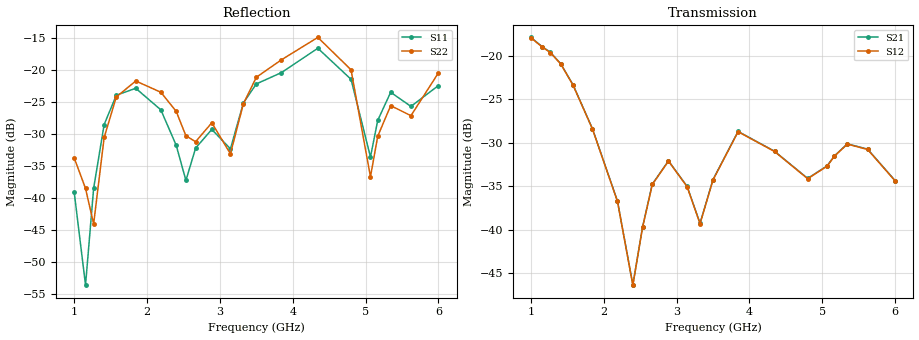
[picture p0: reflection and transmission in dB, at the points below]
!Agilent Technologies,E8364B,MY43040528,A.07.50.67
!Agilent E8364B: A.07.50.67
!Date: Sunday, March 01, 2026 15:36:02
!Correction: S11(Full 2 Port(1,2))
!S21(Full 2 Port(1,2))
!S12(Full 2 Port(1,2))
!S22(Full 2 Port(1,2))
!S2P File: Measurements: S11, S21, S12, S22:
# Hz S  dB  R 50
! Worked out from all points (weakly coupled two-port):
!   451 points, 1 GHz to 6 GHz, reference 50 ohm
!   highest |S21| = -17.88 dB at 1 GHz (marker M1); lowest = -46.4 dB at 2.4 GHz (marker M2)
!   lowest |S11| = -53.6 dB at 1.156 GHz (marker M3), VSWR 1.00, Z = 49.9 + j0.173 ohm
!   |S11| at or under -10 dB: start of sweep to end of sweep
!   |S22| runs from -44.2 to -14.8 dB; largest |S21 - S12| = 0.00053
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1e9  -39.11 33.9  -17.88 27.7  -17.92 27.7  -33.74 -13.1
1.155556e9  -53.64 123.5  -18.95 -18.7  -18.99 -18.7  -38.52 1.5
1.266667e9  -38.50 -163.2  -19.58 -54.2  -19.62 -54.2  -44.07 56.3
1.411111e9  -28.51 176.3  -20.93 -102.8  -20.96 -102.7  -30.54 87.2
1.577778e9  -23.94 139.7  -23.32 -157.7  -23.36 -157.7  -24.21 48.3
1.844444e9  -22.84 88.2  -28.38 119.7  -28.40 119.8  -21.70 -13.6
2.188889e9  -26.21 42.6  -36.72 16.4  -36.76 16.5  -23.46 -74.9
2.4e9  -31.76 22.4  -46.36 -118.5  -46.39 -118.4  -26.45 -108.1
2.533333e9  -37.25 52.5  -39.70 126.0  -39.74 126.2  -30.28 -114.1
2.666667e9  -32.20 82.4  -34.77 62.9  -34.81 62.9  -31.20 -97.0
2.888889e9  -29.28 55.0  -32.09 -27.5  -32.12 -27.4  -28.24 -114.9
3.144444e9  -32.32 83.6  -35.02 -117.4  -35.06 -117.4  -33.10 -107.1
3.322222e9  -25.13 82.3  -39.28 -136.6  -39.32 -136.6  -25.27 -95.6
3.5e9  -22.16 56.4  -34.25 -153.8  -34.29 -153.8  -21.12 -125.8
3.844444e9  -20.39 26.9  -28.70 85.9  -28.74 86.0  -18.39 -171.3
4.344444e9  -16.58 -40.1  -30.98 -94.7  -31.01 -94.7  -14.88 106.4
4.8e9  -21.44 -114.8  -34.11 72.0  -34.15 72.0  -19.95 14.6
5.066667e9  -33.60 -79.1  -32.66 -76.1  -32.70 -76.1  -36.69 21.9
5.166667e9  -27.86 -54.5  -31.52 -127.4  -31.56 -127.3  -30.34 68.9
5.344444e9  -23.47 -75.8  -30.13 149.5  -30.16 149.5  -25.56 44.6
5.622222e9  -25.68 -99.7  -30.74 34.0  -30.78 34.0  -27.13 34.2
6e9  -22.41 -91.0  -34.36 -75.0  -34.40 -75.0  -20.43 3.9
